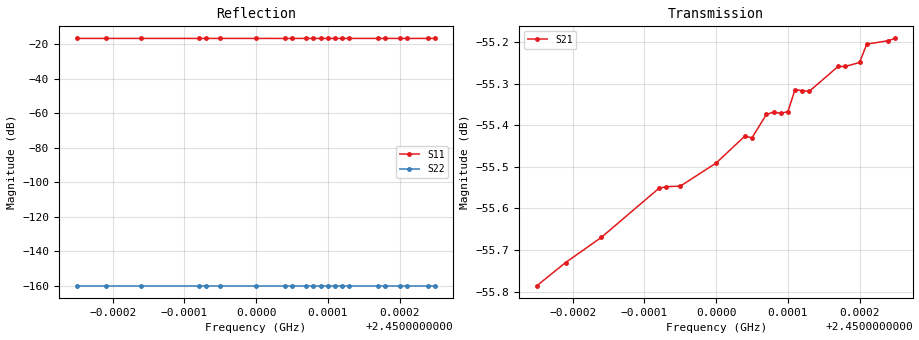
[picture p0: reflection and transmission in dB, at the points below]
! NanoVNA-App
! Date: 2024-02-22 10:33:23
! Start: 2.4498GHz Stop: 2.4503GHz Points: 51
! S-Parameter data: F S11 S21 S12 S22
# Hz S RI R 50
!  Frequency  S11_Real  S11_Imag  S21_Real  S21_Imag  S12_Real  S12_Imag  S22_Real  S22_Imag
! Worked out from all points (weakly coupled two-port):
!   51 points, 2.44975 GHz to 2.45025 GHz, reference 50 ohm
!   highest |S21| = -55.20 dB at 2.45025 GHz (marker M1); lowest = -55.8 dB at 2.44975 GHz (marker M2)
!   lowest |S11| = -16.6 dB at 2.45012 GHz (marker M3), VSWR 1.35, Z = 47.9 - j14.6 ohm
!   |S11| at or under -10 dB: start of sweep to end of sweep
!   S12 and S22 are empty: the file has one direction only
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2.44975e9  0.00167 -0.1495  -0.00157 0.000417  0 0  0 0
2.44979e9  0.00167 -0.149  -0.00158 0.00042  0 0  0 0
2.44984e9  0.00145 -0.1491  -0.00159 0.000427  0 0  0 0
2.44992e9  0.00109 -0.1491  -0.00161 0.000439  0 0  0 0
2.44993e9  0.00116 -0.1488  -0.00161 0.000442  0 0  0 0
2.44995e9  0.00132 -0.1494  -0.00161 0.000443  0 0  0 0
2.45e9  0.00103 -0.1491  -0.00162 0.000447  0 0  0 0
2.45004e9  0.00102 -0.1488  -0.00163 0.000458  0 0  0 0
2.45005e9  0.00076 -0.1488  -0.00163 0.000455  0 0  0 0
2.45007e9  0.00113 -0.1491  -0.00164 0.00046  0 0  0 0
2.45008e9  0.000756 -0.1492  -0.00164 0.000464  0 0  0 0
2.45009e9  0.00103 -0.1489  -0.00164 0.000462  0 0  0 0
2.4501e9  0.000898 -0.1492  -0.00164 0.000465  0 0  0 0
2.45011e9  0.0011 -0.1489  -0.00165 0.000468  0 0  0 0
2.45012e9  0.00106 -0.1487  -0.00165 0.000466  0 0  0 0
2.45013e9  0.00102 -0.1491  -0.00165 0.000465  0 0  0 0
2.45017e9  0.000188 -0.1489  -0.00166 0.000473  0 0  0 0
2.45018e9  0.000633 -0.1491  -0.00166 0.000473  0 0  0 0
2.4502e9  0.000312 -0.1491  -0.00166 0.00048  0 0  0 0
2.45021e9  0.00087 -0.1489  -0.00167 0.000477  0 0  0 0
2.45024e9  7.32e-05 -0.1489  -0.00167 0.000483  0 0  0 0
2.45025e9  0.000229 -0.1498  -0.00167 0.000487  0 0  0 0
